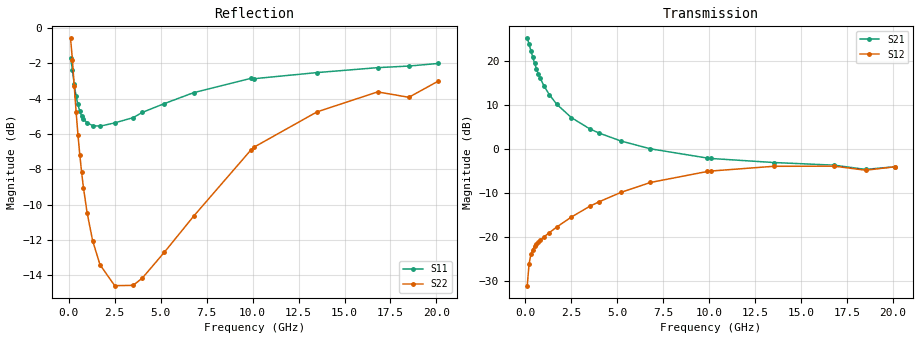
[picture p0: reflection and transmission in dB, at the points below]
!  Infineon Technologies AG
! BFR380L3 , PF131585-7, No.6, Th 09.10.01, soldered on pcb-board, measured with PP GSG850
!  Vce=2.5 V,  Ic=6.0 mA
! Common Emitter S-Parameters:  15. November 2001
#  GHz  S  MA  R  50
! f  S11  S21  S12  S22
! GHz  Mag  Ang  Mag  Ang  Mag  Ang  Mag  Ang
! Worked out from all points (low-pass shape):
!   201 points, 100 MHz to 20.1 GHz, reference 50 ohm
!   highest |S21| = 25.22 dB at 100 MHz (marker M1); lowest = -4.7 dB at 18.5 GHz (marker M2)
!   |S21| within 3 dB of the highest: start of sweep to 311.8 MHz
!   lowest |S11| = -5.6 dB at 1.7 GHz (marker M3), VSWR 3.23, Z = 15.5 - j0.824 ohm
!   |S11| at or under -10 dB: nowhere
!   |S22| runs from -14.8 to -0.6 dB; largest |S21 - S12| = 18
!   S11 on the Smith chart (normalised r, x): 100 MHz: 1.09, -3.04; 400 MHz: 0.36, -0.78; 1 GHz: 0.32, -0.23; 4 GHz: 0.30, +0.35; 9.9 GHz: 0.39, +1.13; 20.1 GHz: 0.95, +2.54
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0.1  0.8241 -32.8  18.24 158.8  0.02767 72.9  0.9343 -19.9
0.2  0.7603 -60.2  15.68 141.5  0.04929 61.0  0.8108 -36.0
0.3  0.6929 -82.3  13.17 128.7  0.0629 53.3  0.6837 -47.4
0.4  0.6399 -99.4  11.1 119.2  0.07139 48.3  0.5799 -55.7
0.5  0.6079 -112.8  9.479 112.0  0.07775 45.7  0.4996 -61.7
0.6  0.5808 -123.9  8.212 106.3  0.0829 44.3  0.4386 -66.3
0.7  0.5636 -132.6  7.236 101.5  0.08713 43.6  0.3909 -69.9
0.8  0.5531 -140.1  6.443 97.5  0.09122 43.6  0.3535 -73.0
1  0.5391 -151.9  5.285 91.0  0.09917 44.3  0.2999 -77.8
1.3  0.5295 -165.2  4.156 83.1  0.1112 46.2  0.2502 -83.8
1.7  0.5274 -177.9  3.243 74.5  0.1288 48.5  0.214 -90.9
2.5  0.5388 163.3  2.28 60.4  0.1676 51.1  0.1867 -104.9
3.5  0.5576 145.7  1.696 45.7  0.2223 50.9  0.1871 -123.1
4  0.5769 138.3  1.521 39.5  0.2498 49.8  0.1961 -133.8
5.2  0.611 122.7  1.233 25.8  0.3204 44.4  0.2321 -155.1
6.8  0.6563 104.5  1.005 11.3  0.4154 35.5  0.2938 176.7
9.9  0.7201 79.2  0.788 -7.5  0.5547 14.8  0.4511 137.1
10.1  0.7187 77.7  0.7797 -8.3  0.561 13.5  0.4608 134.8
13.5  0.7477 59.8  0.7015 -22.4  0.635 -8.6  0.5788 102.3
16.8  0.7721 47.6  0.654 -33.4  0.6374 -25.2  0.6593 79.0
18.5  0.7802 45.6  0.5853 -40.6  0.5729 -33.8  0.6366 72.8
20.1  0.7935 38.6  0.6283 -44.4  0.627 -39.0  0.7074 61.9
